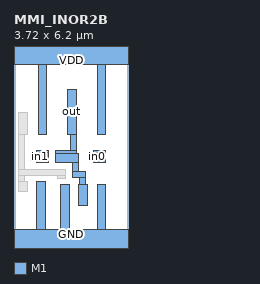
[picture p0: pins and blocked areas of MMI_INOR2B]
MACRO MMI_INOR2B
	CLASS CORE ;
	FOREIGN MMI_INOR2B 0 0 ;
	SIZE 3.72 BY 6.2 ;
	SYMMETRY X Y ;
	SITE CORE1 ;
	PIN out
		DIRECTION output ;
		USE SIGNAL ;
		PORT
			LAYER M1 ;
			RECT 1.745 3.515 2.025 4.985 ;
			LAYER M1 ;
			RECT 1.835 2.98 2.025 3.515 ;
			LAYER M1 ;
			RECT 1.36 2.885 2.025 2.98 ;
			LAYER M1 ;
			RECT 1.36 2.6 2.105 2.885 ;
			LAYER M1 ;
			RECT 1.91 2.31 2.105 2.6 ;
			LAYER M1 ;
			RECT 1.91 2.115 2.32 2.31 ;
			LAYER M1 ;
			RECT 2.125 1.875 2.32 2.115 ;
			LAYER M1 ;
			RECT 2.12 1.175 2.4 1.875 ;
		END
		AntennaDiffArea 1.0164 ;
	END out
	PIN in1
		DIRECTION input ;
		USE SIGNAL ;
		PORT
			LAYER M1 ;
			RECT 0.74 2.93 1.12 2.98 ;
			LAYER M1 ;
			RECT 0.55 2.65 1.12 2.93 ;
			LAYER M1 ;
			RECT 0.74 2.6 1.12 2.65 ;
		END
		AntennaGateArea 0.17325 ;
	END in1
	PIN GND
		DIRECTION inout ;
		USE GROUND ;
		PORT
			LAYER M1 ;
			RECT 0.745 0.42 1.025 1.965 ;
			LAYER M1 ;
			RECT 1.53 0.42 1.81 1.875 ;
			LAYER M1 ;
			RECT 2.71 0.42 2.99 1.875 ;
			LAYER M1 ;
			RECT 0 -0.42 3.72 0.42 ;
		END
	END GND
	PIN VDD
		DIRECTION inout ;
		USE POWER ;
		PORT
			LAYER M1 ;
			RECT 0 5.78 3.72 6.62 ;
			LAYER M1 ;
			RECT 0.785 3.515 1.065 5.78 ;
			LAYER M1 ;
			RECT 2.71 3.515 2.99 5.78 ;
		END
	END VDD
	PIN in0
		DIRECTION input ;
		USE SIGNAL ;
		PORT
			LAYER M1 ;
			RECT 2.6 2.93 2.98 2.98 ;
			LAYER M1 ;
			RECT 2.455 2.65 2.98 2.93 ;
			LAYER M1 ;
			RECT 2.6 2.6 2.98 2.65 ;
		END
		AntennaGateArea 0.5775 ;
	END in0
	OBS
		LAYER M1 ;
		RECT 0.155 3.515 0.435 4.215 ;
		LAYER M1 ;
		RECT 0.155 2.36 0.35 3.515 ;
		LAYER M1 ;
		RECT 0.155 2.165 1.69 2.36 ;
		LAYER M1 ;
		RECT 0.155 1.965 0.35 2.165 ;
		LAYER M1 ;
		RECT 1.405 2.075 1.685 2.165 ;
		LAYER M1 ;
		RECT 0.155 1.65 0.435 1.965 ;
	END
END MMI_INOR2B
